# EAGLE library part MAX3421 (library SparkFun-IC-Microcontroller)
USB Peripheral/Host Controller with SPI Interface

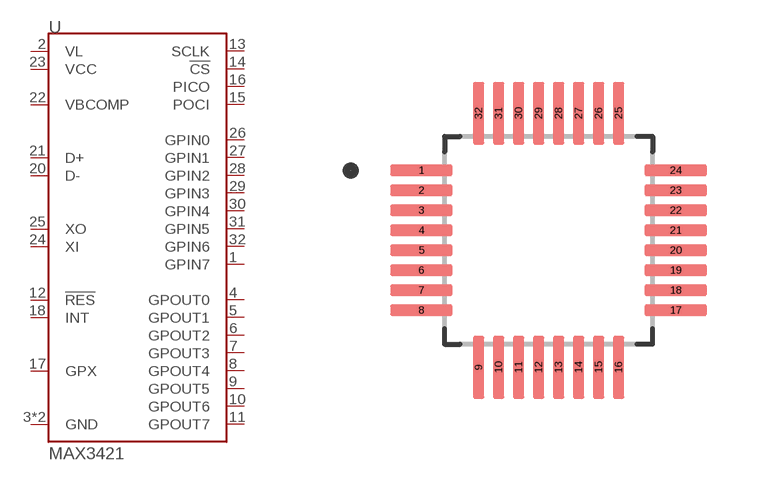
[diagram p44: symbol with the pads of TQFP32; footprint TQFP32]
Designator prefix -

## MAX3421  [TQFP32]
1  GPIN7  in
2  VL  in
3  GND  in
4  GPOUT0  out
5  GPOUT1  out
6  GPOUT2  out
7  GPOUT3  out
8  GPOUT4  out
9  GPOUT5  out
10  GPOUT6  out
11  GPOUT7  out
12  !RES  in
13  SCLK  in
14  !CS  in
15  POCI  out
16  PICO
17  GPX  out
18  INT  out
19  GND  in
20  D-
21  D+
22  VBCOMP  in
23  VCC  in
24  XI  in
25  XO  out
26  GPIN0  in
27  GPIN1  in
28  GPIN2  in
29  GPIN3  in
30  GPIN4  in
31  GPIN5  in
32  GPIN6  in

## Footprint TQFP32 (pad centres in mm)
smd 1.56 x 0.28: 1 -3.18,1.75; 2 -3.18,1.25; 3 -3.18,0.75; 4 -3.18,0.25; 5 -3.18,-0.25; 6 -3.18,-0.75; 7 -3.18,-1.25; 8 -3.18,-1.75; 17 3.18,-1.75; 18 3.18,-1.25; 19 3.18,-0.75; 20 3.18,-0.25; 21 3.18,0.25; 22 3.18,0.75; 23 3.18,1.25; 24 3.18,1.75
smd 0.28 x 1.56: 9 -1.75,-3.18; 10 -1.25,-3.18; 11 -0.75,-3.18; 12 -0.25,-3.18; 13 0.25,-3.18; 14 0.75,-3.18; 15 1.25,-3.18; 16 1.75,-3.18; 25 1.75,3.18; 26 1.25,3.18; 27 0.75,3.18; 28 0.25,3.18; 29 -0.25,3.18; 30 -0.75,3.18; 31 -1.25,3.18; 32 -1.75,3.18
